! (c) 2009  Infineon Technologies AG, Munich
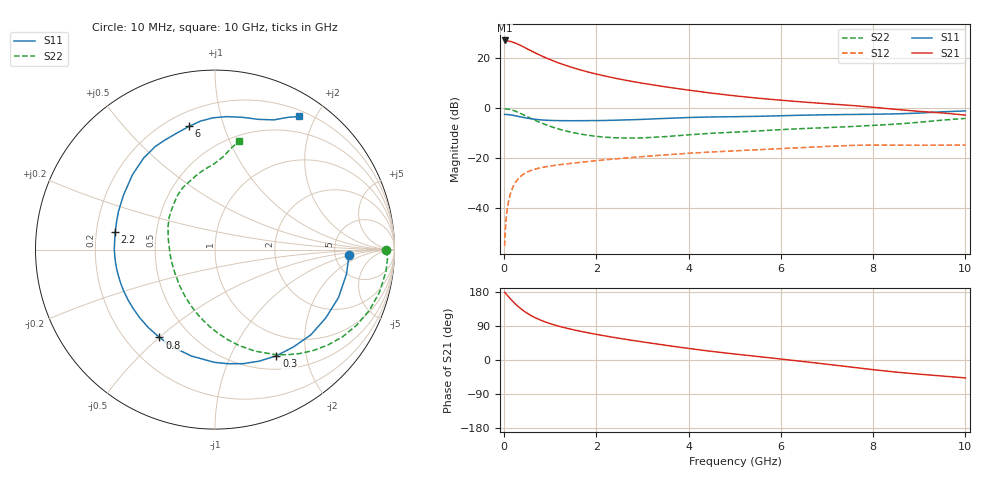
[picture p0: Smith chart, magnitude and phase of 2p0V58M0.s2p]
! Infineon Technologies  Discrete & RF Semiconductors
! BFP420
! VCE =  0.5 V,  IC =  8.0 mA
! Common Emitter S-Parameters:  Nov 2009
# GHz  S  MA  R  50
!  f  S11  S21  S12  S22
! GHz  MAG  ANG  MAG  ANG  MAG  ANG  MAG  ANG
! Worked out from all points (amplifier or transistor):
!   46 points, 10 MHz to 10 GHz, reference 50 ohm
!   highest |S21| = 27.1 dB at 10 MHz (marker M1)
!   |S21| within 3 dB of that: start of sweep to 462.7 MHz
!   unconditionally stable (mu >= 1): 2.451 GHz to end of sweep
!   at 300 MHz: K = 0.17, MSG = 27.0 dB, |S12| = -28.5 dB
!   at 1.7 GHz: K = 0.79, MSG = 18.4 dB, |S12| = -21.7 dB
!   at 10 GHz: K = 1.07, MAG = 4.4 dB, |S12| = -14.8 dB
!   lowest NFmin = 0.79 dB at 900 MHz
!   S11 on the Smith chart (normalised r, x): 10 MHz: 6.75, -0.95; 300 MHz: 0.68, -1.51; 800 MHz: 0.34, -0.50; 2.2 GHz: 0.28, +0.08; 6 GHz: 0.29, +0.77; 10 GHz: 0.28, +1.78
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0.01  0.7464 -2.4  22.69 179.2  0.0017 110.9  0.9541 -0.2
0.02  0.7453 -4.5  22.24 177.6  0.0031 89.4  0.9627 -2.8
0.1  0.7381 -21.2  22.09 166.3  0.0144 79.6  0.9471 -14.4
0.15  0.7252 -31.7  21.52 159.5  0.0212 74.5  0.9245 -21.5
0.2  0.7146 -41.6  20.81 153.2  0.0273 69.9  0.8945 -28.1
0.25  0.6967 -51.0  19.91 147.1  0.0329 65.6  0.8608 -34.4
0.3  0.6835 -60.0  19.05 141.6  0.0378 61.6  0.8228 -40.3
0.4  0.6546 -76.1  17.2 131.8  0.0459 54.9  0.7465 -50.9
0.5  0.6281 -90.3  15.42 123.4  0.0521 49.6  0.6738 -60.2
0.6  0.6073 -102.6  13.84 116.1  0.0569 45.4  0.6094 -68.3
0.8  0.5792 -122.3  11.24 104.8  0.0638 39.6  0.5056 -82.1
1  0.5658 -137.8  9.347 95.9  0.0688 36.1  0.4306 -93.8
1.2  0.5597 -150.1  7.925 88.7  0.0731 33.7  0.3763 -104.4
1.7  0.5589 -173.0  5.671 74.7  0.0825 30.2  0.2965 -127.4
2.2  0.5648 170.0  4.364 63.3  0.0919 27.7  0.2601 -148.1
2.8  0.5846 153.6  3.389 51.5  0.1027 24.5  0.2507 -171.3
3.5  0.6211 137.7  2.66 38.9  0.1152 20.2  0.268 166.5
5.5  0.6834 108.0  1.579 9.2  0.1461 6.8  0.3474 130.5
6  0.7016 101.9  1.438 2.6  0.1538 3.3  0.3694 123.9
7  0.7342 90.9  1.221 -11.2  0.1702 -4.9  0.4048 110.7
8.5  0.7648 71.6  0.94 -32.0  0.1802 -20.4  0.4762 90.9
10  0.8766 57.8  0.723 -47.3  0.1813 -30.1  0.6197 77.4
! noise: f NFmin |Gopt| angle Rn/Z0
0.9  0.79  0.08  30  0.13
1.8  1.14  0.06  171  0.12
2.4  1.24  0.1  160  0.13
3  1.32  0.17  -165  0.12
4  1.46  0.32  -132  0.14
5  1.85  0.39  -110  0.25
6  2.3  0.46  -95  0.37
